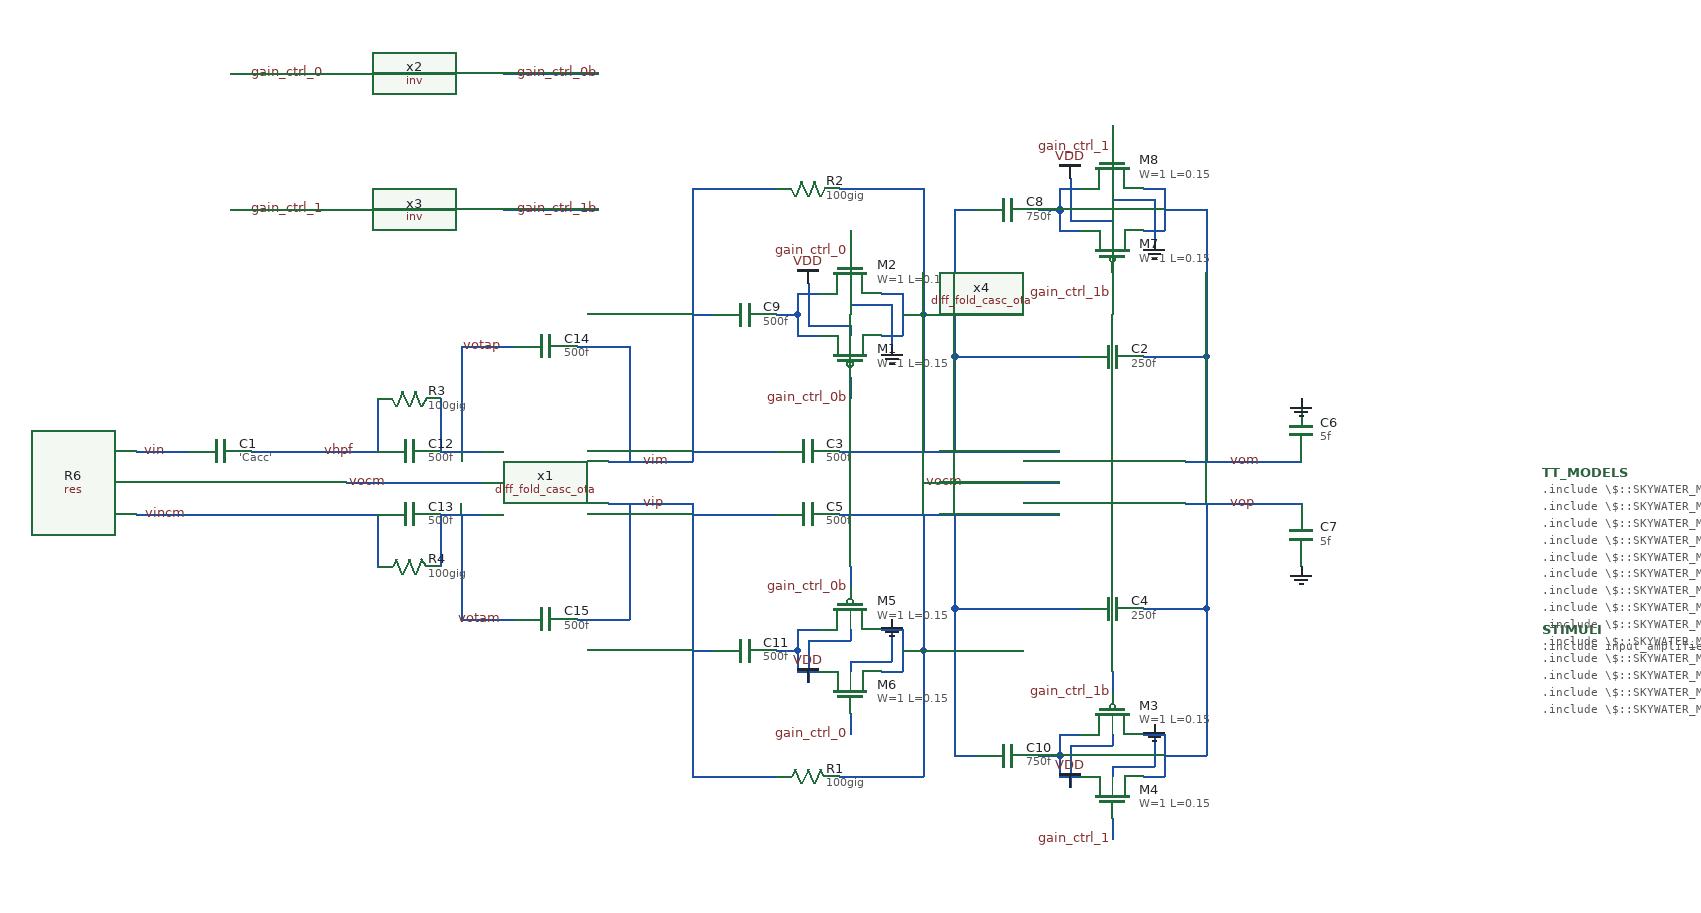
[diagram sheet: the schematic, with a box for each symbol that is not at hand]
v {xschem version=2.9.9 file_version=1.2 

* Copyright 2020 Stefan Frederik Schippers
* 
* Licensed under the Apache License, Version 2.0 (the "License");
* you may not use this file except in compliance with the License.
* You may obtain a copy of the License at
*
*     https://www.apache.org/licenses/LICENSE-2.0
*
* Unless required by applicable law or agreed to in writing, software
* distributed under the License is distributed on an "AS IS" BASIS,
* WITHOUT WARRANTIES OR CONDITIONS OF ANY KIND, either express or implied.
* See the License for the specific language governing permissions and
* limitations under the License.

}
G {}
K {}
V {}
S {}
E {}
N 970 -630 1030 -630 { lab=vom}
N 1030 -630 1030 -530 { lab=vom}
N 1010 -490 1120 -490 { lab=vop}
N 1010 -530 1120 -530 { lab=vom}
N 890 -790 890 -770 { lab=#net1}
N 890 -790 910 -790 { lab=#net1}
N 890 -770 890 -750 { lab=#net1}
N 890 -750 910 -750 { lab=#net1}
N 970 -790 990 -790 { lab=vom}
N 990 -790 990 -750 { lab=vom}
N 970 -750 990 -750 { lab=vom}
N 940 -760 940 -750 { lab=VDD}
N 940 -790 940 -780 { lab=GND}
N 940 -780 980 -780 { lab=GND}
N 980 -780 980 -740 { lab=GND}
N 900 -800 900 -760 { lab=VDD}
N 900 -760 940 -760 { lab=VDD}
N 870 -770 890 -770 { lab=#net1}
N 940 -850 940 -830 { lab=gain_ctrl_1}
N 940 -710 940 -690 { lab=gain_ctrl_1b}
N 790 -630 910 -630 { lab=#net2}
N 790 -630 790 -540 { lab=#net2}
N 790 -770 810 -770 { lab=#net2}
N 790 -770 790 -630 { lab=#net2}
N 990 -770 1030 -770 { lab=vom}
N 1030 -770 1030 -630 { lab=vom}
N 640 -690 640 -670 { lab=#net3}
N 640 -690 660 -690 { lab=#net3}
N 640 -670 640 -650 { lab=#net3}
N 640 -650 660 -650 { lab=#net3}
N 720 -690 740 -690 { lab=#net2}
N 740 -690 740 -650 { lab=#net2}
N 720 -650 740 -650 { lab=#net2}
N 690 -660 690 -650 { lab=VDD}
N 690 -690 690 -680 { lab=GND}
N 690 -680 730 -680 { lab=GND}
N 730 -680 730 -640 { lab=GND}
N 650 -700 650 -660 { lab=VDD}
N 650 -660 690 -660 { lab=VDD}
N 620 -670 640 -670 { lab=#net3}
N 690 -750 690 -730 { lab=gain_ctrl_0}
N 690 -610 690 -590 { lab=gain_ctrl_0b}
N 680 -540 890 -540 { lab=#net2}
N 740 -670 760 -670 { lab=#net2}
N 760 -670 760 -540 { lab=#net2}
N 680 -790 760 -790 { lab=#net2}
N 760 -790 760 -670 { lab=#net2}
N 540 -790 620 -790 { lab=vim}
N 540 -670 560 -670 { lab=vim}
N 970 -390 1030 -390 { lab=vop}
N 1030 -490 1030 -390 { lab=vop}
N 890 -250 890 -230 { lab=#net4}
N 890 -230 910 -230 { lab=#net4}
N 890 -270 890 -250 { lab=#net4}
N 890 -270 910 -270 { lab=#net4}
N 970 -230 990 -230 { lab=vop}
N 990 -270 990 -230 { lab=vop}
N 970 -270 990 -270 { lab=vop}
N 940 -270 940 -260 { lab=VDD}
N 940 -240 940 -230 { lab=GND}
N 940 -240 980 -240 { lab=GND}
N 980 -280 980 -240 { lab=GND}
N 900 -260 900 -220 { lab=VDD}
N 900 -260 940 -260 { lab=VDD}
N 870 -250 890 -250 { lab=#net4}
N 940 -190 940 -170 { lab=gain_ctrl_1}
N 940 -330 940 -310 { lab=gain_ctrl_1b}
N 790 -390 910 -390 { lab=#net5}
N 790 -480 790 -390 { lab=#net5}
N 790 -250 810 -250 { lab=#net5}
N 790 -390 790 -250 { lab=#net5}
N 990 -250 1030 -250 { lab=vop}
N 1030 -390 1030 -250 { lab=vop}
N 640 -350 640 -330 { lab=#net6}
N 640 -330 660 -330 { lab=#net6}
N 640 -370 640 -350 { lab=#net6}
N 640 -370 660 -370 { lab=#net6}
N 720 -330 740 -330 { lab=#net5}
N 740 -370 740 -330 { lab=#net5}
N 720 -370 740 -370 { lab=#net5}
N 690 -370 690 -360 { lab=VDD}
N 690 -340 690 -330 { lab=GND}
N 690 -340 730 -340 { lab=GND}
N 730 -380 730 -340 { lab=GND}
N 650 -360 650 -320 { lab=VDD}
N 650 -360 690 -360 { lab=VDD}
N 620 -350 640 -350 { lab=#net6}
N 690 -290 690 -270 { lab=gain_ctrl_0}
N 690 -430 690 -410 { lab=gain_ctrl_0b}
N 680 -480 890 -480 { lab=#net5}
N 740 -350 760 -350 { lab=#net5}
N 760 -480 760 -350 { lab=#net5}
N 680 -230 760 -230 { lab=#net5}
N 760 -350 760 -230 { lab=#net5}
N 540 -230 620 -230 { lab=vip}
N 540 -350 560 -350 { lab=vip}
N 100 -900 200 -900 { lab=gain_ctrl_0}
N 360 -900 450 -900 { lab=gain_ctrl_0b}
N 100 -770 200 -770 { lab=gain_ctrl_1}
N 360 -770 450 -770 { lab=gain_ctrl_1b}
N 300 -540 340 -540 { lab=votap}
N 300 -480 340 -480 { lab=votam}
N 320 -480 320 -380 { lab=votam}
N 320 -380 370 -380 { lab=votam}
N 320 -640 320 -540 { lab=votap}
N 320 -640 370 -640 { lab=votap}
N 300 -590 300 -540 { lab=votap}
N 240 -590 240 -540 { lab=vhpf}
N 300 -480 300 -430 { lab=votam}
N 240 -480 240 -430 { lab=vincm}
N 210 -510 340 -510 { lab=vocm}
N 430 -640 480 -640 { lab=vim}
N 480 -640 480 -530 { lab=vim}
N 430 -380 480 -380 { lab=vip}
N 480 -490 480 -380 { lab=vip}
N 460 -530 540 -530 { lab=vim}
N 460 -490 540 -490 { lab=vip}
N 120 -540 240 -540 { lab=vhpf}
N 10 -480 240 -480 { lab=vincm}
N 10 -540 60 -540 { lab=vin}
N 760 -510 890 -510 { lab=vocm}
N 540 -490 540 -230 { lab=vip}
N 540 -790 540 -530 { lab=vim}
N 540 -540 620 -540 { lab=vim}
N 540 -480 620 -480 { lab=vip}
C {devices/title.sym} 160 -30 0 0 {name=l1 author="Nikhil Poole"}
C {devices/code.sym} 1350 -370 0 0 {name=STIMULI 
only_toplevel=true
place=end
value=".include input_amplifier_commands.spice"}
C {devices/code.sym} 1350 -520 0 0 {name=TT_MODELS
only_toplevel=true
format="tcleval( @value )"
value="
.include \\\\$::SKYWATER_MODELS\\\\/cells/nfet_01v8/sky130_fd_pr__nfet_01v8__tt.corner.spice
.include \\\\$::SKYWATER_MODELS\\\\/cells/nfet_01v8_lvt/sky130_fd_pr__nfet_01v8_lvt__tt.corner.spice
.include \\\\$::SKYWATER_MODELS\\\\/cells/pfet_01v8/sky130_fd_pr__pfet_01v8__tt.corner.spice
.include \\\\$::SKYWATER_MODELS\\\\/cells/nfet_03v3_nvt/sky130_fd_pr__nfet_03v3_nvt__tt.corner.spice
.include \\\\$::SKYWATER_MODELS\\\\/cells/nfet_05v0_nvt/sky130_fd_pr__nfet_05v0_nvt__tt.corner.spice
.include \\\\$::SKYWATER_MODELS\\\\/cells/esd_nfet_01v8/sky130_fd_pr__esd_nfet_01v8__tt.corner.spice
.include \\\\$::SKYWATER_MODELS\\\\/cells/pfet_01v8_lvt/sky130_fd_pr__pfet_01v8_lvt__tt.corner.spice
.include \\\\$::SKYWATER_MODELS\\\\/cells/pfet_01v8_hvt/sky130_fd_pr__pfet_01v8_hvt__tt.corner.spice
.include \\\\$::SKYWATER_MODELS\\\\/cells/esd_pfet_g5v0d10v5/sky130_fd_pr__esd_pfet_g5v0d10v5__tt.corner.spice
.include \\\\$::SKYWATER_MODELS\\\\/cells/pfet_g5v0d10v5/sky130_fd_pr__pfet_g5v0d10v5__tt.corner.spice
.include \\\\$::SKYWATER_MODELS\\\\/cells/pfet_g5v0d16v0/sky130_fd_pr__pfet_g5v0d16v0__tt.corner.spice
.include \\\\$::SKYWATER_MODELS\\\\/cells/nfet_g5v0d10v5/sky130_fd_pr__nfet_g5v0d10v5__tt.corner.spice
.include \\\\$::SKYWATER_MODELS\\\\/cells/nfet_g5v0d16v0/sky130_fd_pr__nfet_g5v0d16v0__tt_discrete.corner.spice
.include \\\\$::SKYWATER_MODELS\\\\/cells/esd_nfet_g5v0d10v5/sky130_fd_pr__esd_nfet_g5v0d10v5__tt.corner.spice
.include \\\\$::SKYWATER_MODELS\\\\/models/corners/tt/nonfet.spice
* Mismatch parameters
.include \\\\$::SKYWATER_MODELS\\\\/cells/nfet_01v8/sky130_fd_pr__nfet_01v8__mismatch.corner.spice
.include \\\\$::SKYWATER_MODELS\\\\/cells/pfet_01v8/sky130_fd_pr__pfet_01v8__mismatch.corner.spice
.include \\\\$::SKYWATER_MODELS\\\\/cells/nfet_01v8_lvt/sky130_fd_pr__nfet_01v8_lvt__mismatch.corner.spice
.include \\\\$::SKYWATER_MODELS\\\\/cells/pfet_01v8_lvt/sky130_fd_pr__pfet_01v8_lvt__mismatch.corner.spice
.include \\\\$::SKYWATER_MODELS\\\\/cells/pfet_01v8_hvt/sky130_fd_pr__pfet_01v8_hvt__mismatch.corner.spice
.include \\\\$::SKYWATER_MODELS\\\\/cells/nfet_g5v0d10v5/sky130_fd_pr__nfet_g5v0d10v5__mismatch.corner.spice
.include \\\\$::SKYWATER_MODELS\\\\/cells/pfet_g5v0d10v5/sky130_fd_pr__pfet_g5v0d10v5__mismatch.corner.spice
.include \\\\$::SKYWATER_MODELS\\\\/cells/nfet_05v0_nvt/sky130_fd_pr__nfet_05v0_nvt__mismatch.corner.spice
.include \\\\$::SKYWATER_MODELS\\\\/cells/nfet_03v3_nvt/sky130_fd_pr__nfet_03v3_nvt__mismatch.corner.spice
* Resistor\\\\$::SKYWATER_MODELS\\\\/Capacitor
.include \\\\$::SKYWATER_MODELS\\\\/models/r+c/res_typical__cap_typical.spice
.include \\\\$::SKYWATER_MODELS\\\\/models/r+c/res_typical__cap_typical__lin.spice
* Special cells
.include \\\\$::SKYWATER_MODELS\\\\/models/corners/tt/specialized_cells.spice
* All models
.include \\\\$::SKYWATER_MODELS\\\\/models/all.spice
* Corner
.include \\\\$::SKYWATER_MODELS\\\\/models/corners/tt/rf.spice
"}
C {devices/lab_wire.sym} 40 -540 0 0 {name=l13 sig_type=std_logic lab=vin}
C {devices/capa.sym} 90 -540 3 0 {name=C1
m=1
value='Cacc'
footprint=1206
device="ceramic capacitor"}
C {devices/capa.sym} 940 -630 1 1 {name=C2
m=1
value=250f
footprint=1206
device="ceramic capacitor"}
C {devices/capa.sym} 650 -540 1 1 {name=C3
m=1
value=500f
footprint=1206
device="ceramic capacitor"}
C {devices/lab_wire.sym} 1050 -530 0 1 {name=l7 sig_type=std_logic lab=vom}
C {devices/lab_wire.sym} 1050 -490 0 1 {name=l8 sig_type=std_logic lab=vop}
C {devices/capa.sym} 1120 -560 2 1 {name=C6
m=1
value=5f
footprint=1206
device="ceramic capacitor"}
C {devices/capa.sym} 1120 -460 0 0 {name=C7
m=1
value=5f
footprint=1206
device="ceramic capacitor"}
C {devices/gnd.sym} 1120 -590 2 1 {name=l9 lab=GND}
C {devices/gnd.sym} 1120 -430 0 0 {name=l10 lab=GND}
C {devices/lab_wire.sym} 360 -640 0 0 {name=l4 sig_type=std_logic lab=votap}
C {devices/res.sym} 650 -790 1 0 {name=R2
value=100gig
footprint=1206
device=resistor
m=1}
C {devices/res.sym} 160 -510 0 0 {name=R6
value='Rhpf'
footprint=1206
device=resistor
m=1}
C {sky130_fd_pr/pfet_01v8_hvt.sym} 940 -730 3 0 {name=M7
L=0.15
W=1
nf=1
mult=1
ad="'int((nf+1)/2) * W/nf * 0.29'" 
pd="'2*int((nf+1)/2) * (W/nf + 0.29)'"
as="'int((nf+2)/2) * W/nf * 0.29'" 
ps="'2*int((nf+2)/2) * (W/nf + 0.29)'"
nrd="'0.29 / W'" nrs="'0.29 / W'"
sa=0 sb=0 sd=0
model=pfet_01v8_hvt
spiceprefix=X
}
C {sky130_fd_pr/nfet_01v8.sym} 940 -810 3 1 {name=M8
L=0.15
W=1
nf=1 
mult=1
ad="'int((nf+1)/2) * W/nf * 0.29'" 
pd="'2*int((nf+1)/2) * (W/nf + 0.29)'"
as="'int((nf+2)/2) * W/nf * 0.29'" 
ps="'2*int((nf+2)/2) * (W/nf + 0.29)'"
nrd="'0.29 / W'" nrs="'0.29 / W'"
sa=0 sb=0 sd=0
model=nfet_01v8
spiceprefix=X
}
C {devices/vdd.sym} 900 -800 0 0 {name=l121 lab=VDD}
C {devices/gnd.sym} 980 -740 0 0 {name=l122 lab=GND}
C {devices/capa.sym} 840 -770 1 1 {name=C8
m=1
value=750f
footprint=1206
device="ceramic capacitor"}
C {sky130_fd_pr/pfet_01v8_hvt.sym} 690 -630 3 0 {name=M1
L=0.15
W=1
nf=1
mult=1
ad="'int((nf+1)/2) * W/nf * 0.29'" 
pd="'2*int((nf+1)/2) * (W/nf + 0.29)'"
as="'int((nf+2)/2) * W/nf * 0.29'" 
ps="'2*int((nf+2)/2) * (W/nf + 0.29)'"
nrd="'0.29 / W'" nrs="'0.29 / W'"
sa=0 sb=0 sd=0
model=pfet_01v8_hvt
spiceprefix=X
}
C {sky130_fd_pr/nfet_01v8.sym} 690 -710 3 1 {name=M2
L=0.15
W=1
nf=1 
mult=1
ad="'int((nf+1)/2) * W/nf * 0.29'" 
pd="'2*int((nf+1)/2) * (W/nf + 0.29)'"
as="'int((nf+2)/2) * W/nf * 0.29'" 
ps="'2*int((nf+2)/2) * (W/nf + 0.29)'"
nrd="'0.29 / W'" nrs="'0.29 / W'"
sa=0 sb=0 sd=0
model=nfet_01v8
spiceprefix=X
}
C {devices/vdd.sym} 650 -700 0 0 {name=l6 lab=VDD}
C {devices/gnd.sym} 730 -640 0 0 {name=l11 lab=GND}
C {devices/capa.sym} 590 -670 1 1 {name=C9
m=1
value=500f
footprint=1206
device="ceramic capacitor"}
C {devices/capa.sym} 940 -390 1 0 {name=C4
m=1
value=250f
footprint=1206
device="ceramic capacitor"}
C {devices/capa.sym} 650 -480 1 0 {name=C5
m=1
value=500f
footprint=1206
device="ceramic capacitor"}
C {devices/lab_wire.sym} 360 -380 2 1 {name=l5 sig_type=std_logic lab=votam}
C {devices/res.sym} 650 -230 1 1 {name=R1
value=100gig
footprint=1206
device=resistor
m=1}
C {sky130_fd_pr/pfet_01v8_hvt.sym} 940 -290 3 1 {name=M3
L=0.15
W=1
nf=1
mult=1
ad="'int((nf+1)/2) * W/nf * 0.29'" 
pd="'2*int((nf+1)/2) * (W/nf + 0.29)'"
as="'int((nf+2)/2) * W/nf * 0.29'" 
ps="'2*int((nf+2)/2) * (W/nf + 0.29)'"
nrd="'0.29 / W'" nrs="'0.29 / W'"
sa=0 sb=0 sd=0
model=pfet_01v8_hvt
spiceprefix=X
}
C {sky130_fd_pr/nfet_01v8.sym} 940 -210 3 0 {name=M4
L=0.15
W=1
nf=1 
mult=1
ad="'int((nf+1)/2) * W/nf * 0.29'" 
pd="'2*int((nf+1)/2) * (W/nf + 0.29)'"
as="'int((nf+2)/2) * W/nf * 0.29'" 
ps="'2*int((nf+2)/2) * (W/nf + 0.29)'"
nrd="'0.29 / W'" nrs="'0.29 / W'"
sa=0 sb=0 sd=0
model=nfet_01v8
spiceprefix=X
}
C {devices/vdd.sym} 900 -220 2 1 {name=l12 lab=VDD}
C {devices/gnd.sym} 980 -280 2 1 {name=l14 lab=GND}
C {devices/capa.sym} 840 -250 1 0 {name=C10
m=1
value=750f
footprint=1206
device="ceramic capacitor"}
C {sky130_fd_pr/pfet_01v8_hvt.sym} 690 -390 3 1 {name=M5
L=0.15
W=1
nf=1
mult=1
ad="'int((nf+1)/2) * W/nf * 0.29'" 
pd="'2*int((nf+1)/2) * (W/nf + 0.29)'"
as="'int((nf+2)/2) * W/nf * 0.29'" 
ps="'2*int((nf+2)/2) * (W/nf + 0.29)'"
nrd="'0.29 / W'" nrs="'0.29 / W'"
sa=0 sb=0 sd=0
model=pfet_01v8_hvt
spiceprefix=X
}
C {sky130_fd_pr/nfet_01v8.sym} 690 -310 3 0 {name=M6
L=0.15
W=1
nf=1 
mult=1
ad="'int((nf+1)/2) * W/nf * 0.29'" 
pd="'2*int((nf+1)/2) * (W/nf + 0.29)'"
as="'int((nf+2)/2) * W/nf * 0.29'" 
ps="'2*int((nf+2)/2) * (W/nf + 0.29)'"
nrd="'0.29 / W'" nrs="'0.29 / W'"
sa=0 sb=0 sd=0
model=nfet_01v8
spiceprefix=X
}
C {devices/vdd.sym} 650 -320 2 1 {name=l15 lab=VDD}
C {devices/gnd.sym} 730 -380 2 1 {name=l16 lab=GND}
C {devices/capa.sym} 590 -350 1 0 {name=C11
m=1
value=500f
footprint=1206
device="ceramic capacitor"}
C {devices/lab_wire.sym} 190 -900 0 0 {name=l17 sig_type=std_logic lab=gain_ctrl_0}
C {/home/users/nhpoole/ee272b/ee272b_mixed_signal_mmwave_accelerator/designs/inv.sym} 250 -900 0 0 {name=x2 M=1}
C {devices/lab_wire.sym} 370 -900 0 1 {name=l18 sig_type=std_logic lab=gain_ctrl_0b}
C {devices/lab_wire.sym} 690 -730 0 0 {name=l19 sig_type=std_logic lab=gain_ctrl_0}
C {devices/lab_wire.sym} 690 -590 0 0 {name=l20 sig_type=std_logic lab=gain_ctrl_0b}
C {devices/lab_wire.sym} 690 -410 0 0 {name=l21 sig_type=std_logic lab=gain_ctrl_0b}
C {devices/lab_wire.sym} 690 -270 0 0 {name=l22 sig_type=std_logic lab=gain_ctrl_0}
C {devices/lab_wire.sym} 190 -770 0 0 {name=l23 sig_type=std_logic lab=gain_ctrl_1}
C {/home/users/nhpoole/ee272b/ee272b_mixed_signal_mmwave_accelerator/designs/inv.sym} 250 -770 0 0 {name=x3 M=1}
C {devices/lab_wire.sym} 370 -770 0 1 {name=l24 sig_type=std_logic lab=gain_ctrl_1b}
C {devices/lab_wire.sym} 940 -830 0 0 {name=l25 sig_type=std_logic lab=gain_ctrl_1}
C {devices/lab_wire.sym} 940 -170 0 0 {name=l26 sig_type=std_logic lab=gain_ctrl_1}
C {devices/lab_wire.sym} 940 -690 0 0 {name=l27 sig_type=std_logic lab=gain_ctrl_1b}
C {devices/lab_wire.sym} 940 -310 0 0 {name=l28 sig_type=std_logic lab=gain_ctrl_1b}
C {devices/lab_wire.sym} 60 -480 0 0 {name=l3 sig_type=std_logic lab=vincm}
C {devices/capa.sym} 270 -540 1 1 {name=C12
m=1
value=500f
footprint=1206
device="ceramic capacitor"}
C {devices/capa.sym} 270 -480 1 0 {name=C13
m=1
value=500f
footprint=1206
device="ceramic capacitor"}
C {devices/capa.sym} 400 -640 1 1 {name=C14
m=1
value=500f
footprint=1206
device="ceramic capacitor"}
C {devices/capa.sym} 400 -380 1 0 {name=C15
m=1
value=500f
footprint=1206
device="ceramic capacitor"}
C {devices/res.sym} 270 -590 1 0 {name=R3
value=100gig
footprint=1206
device=resistor
m=1}
C {devices/res.sym} 270 -430 1 1 {name=R4
value=100gig
footprint=1206
device=resistor
m=1}
C {devices/lab_wire.sym} 490 -530 0 1 {name=l30 sig_type=std_logic lab=vim}
C {devices/lab_wire.sym} 490 -490 0 1 {name=l31 sig_type=std_logic lab=vip}
C {devices/lab_wire.sym} 250 -510 0 0 {name=l33 sig_type=std_logic lab=vocm}
C {devices/lab_wire.sym} 800 -510 0 0 {name=l2 sig_type=std_logic lab=vocm}
C {devices/lab_wire.sym} 220 -540 0 0 {name=l29 sig_type=std_logic lab=vhpf}
C {/home/users/nhpoole/ee272b/ee272b_mixed_signal_mmwave_accelerator/designs/diff_fold_casc_ota.sym} 400 -510 0 0 {name=x1 Lbias='Lbias_diff' Ibias=10u Itail=10u Ccomp=2p}
C {/home/users/nhpoole/ee272b/ee272b_mixed_signal_mmwave_accelerator/designs/diff_fold_casc_ota.sym} 950 -510 0 0 {name=x4 Lbias='Lbias_diff' Ibias=10u Itail=10u Ccomp=2p}
